# Generated by FakeRAM 2.0
VERSION 5.7 ;
BUSBITCHARS "[]" ;
PROPERTYDEFINITIONS
  MACRO width INTEGER ;
  MACRO depth INTEGER ;
  MACRO banks INTEGER ;
END PROPERTYDEFINITIONS
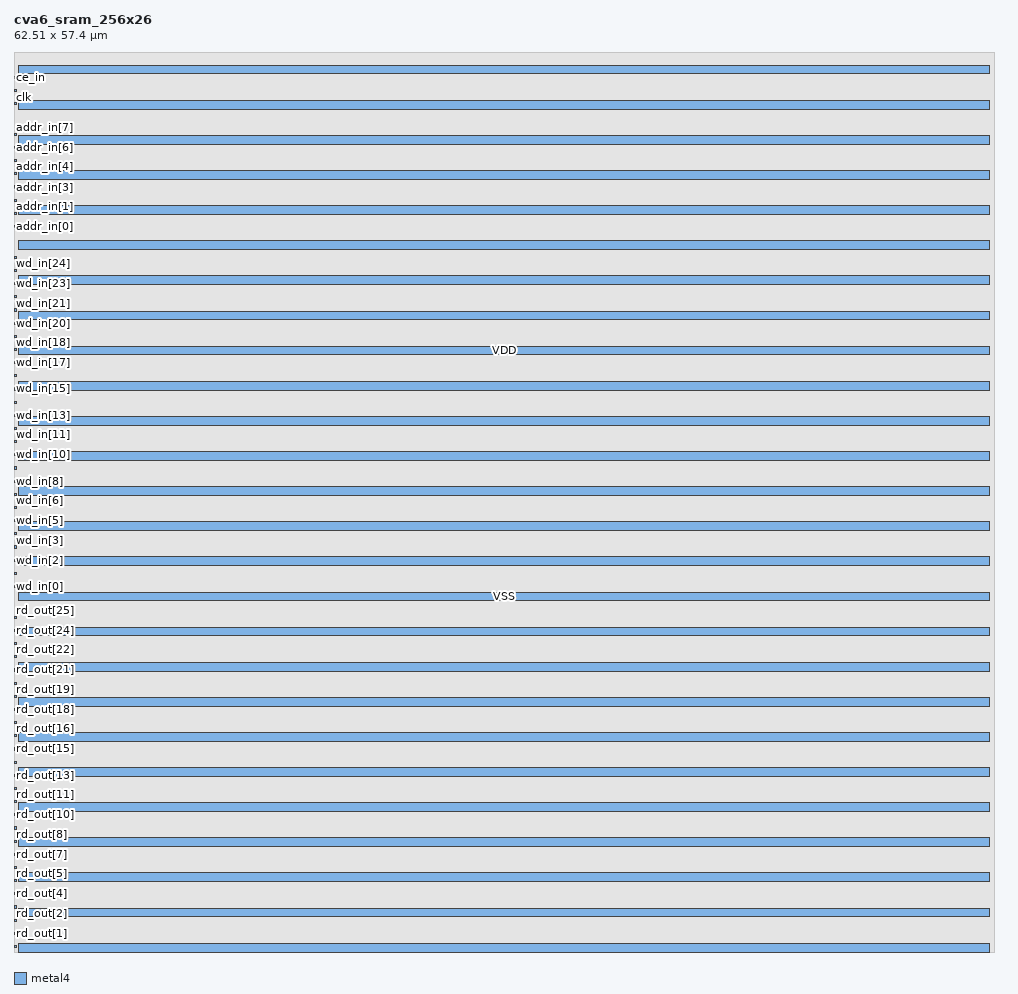
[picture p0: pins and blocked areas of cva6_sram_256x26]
MACRO cva6_sram_256x26
  PROPERTY width 26 ;
  PROPERTY depth 256 ;
  PROPERTY banks 1 ;
  FOREIGN cva6_sram_256x26 0 0 ;
  SYMMETRY X Y R90 ;
  SIZE 62.5100 BY 57.4000 ;
  CLASS BLOCK ;
  PIN rd_out[0]
    DIRECTION OUTPUT ;
    USE SIGNAL ;
    PORT
      LAYER metal4 ;
      RECT 0.00000 0.28000 0.14000 0.42000 ;
    END
  END rd_out[0]
  PIN rd_out[1]
    DIRECTION OUTPUT ;
    USE SIGNAL ;
    PORT
      LAYER metal4 ;
      RECT 0.00000 1.12000 0.14000 1.26000 ;
    END
  END rd_out[1]
  PIN rd_out[2]
    DIRECTION OUTPUT ;
    USE SIGNAL ;
    PORT
      LAYER metal4 ;
      RECT 0.00000 1.96000 0.14000 2.10000 ;
    END
  END rd_out[2]
  PIN rd_out[3]
    DIRECTION OUTPUT ;
    USE SIGNAL ;
    PORT
      LAYER metal4 ;
      RECT 0.00000 2.80000 0.14000 2.94000 ;
    END
  END rd_out[3]
  PIN rd_out[4]
    DIRECTION OUTPUT ;
    USE SIGNAL ;
    PORT
      LAYER metal4 ;
      RECT 0.00000 3.64000 0.14000 3.78000 ;
    END
  END rd_out[4]
  PIN rd_out[5]
    DIRECTION OUTPUT ;
    USE SIGNAL ;
    PORT
      LAYER metal4 ;
      RECT 0.00000 4.48000 0.14000 4.62000 ;
    END
  END rd_out[5]
  PIN rd_out[6]
    DIRECTION OUTPUT ;
    USE SIGNAL ;
    PORT
      LAYER metal4 ;
      RECT 0.00000 5.32000 0.14000 5.46000 ;
    END
  END rd_out[6]
  PIN rd_out[7]
    DIRECTION OUTPUT ;
    USE SIGNAL ;
    PORT
      LAYER metal4 ;
      RECT 0.00000 6.16000 0.14000 6.30000 ;
    END
  END rd_out[7]
  PIN rd_out[8]
    DIRECTION OUTPUT ;
    USE SIGNAL ;
    PORT
      LAYER metal4 ;
      RECT 0.00000 7.00000 0.14000 7.14000 ;
    END
  END rd_out[8]
  PIN rd_out[9]
    DIRECTION OUTPUT ;
    USE SIGNAL ;
    PORT
      LAYER metal4 ;
      RECT 0.00000 7.84000 0.14000 7.98000 ;
    END
  END rd_out[9]
  PIN rd_out[10]
    DIRECTION OUTPUT ;
    USE SIGNAL ;
    PORT
      LAYER metal4 ;
      RECT 0.00000 8.68000 0.14000 8.82000 ;
    END
  END rd_out[10]
  PIN rd_out[11]
    DIRECTION OUTPUT ;
    USE SIGNAL ;
    PORT
      LAYER metal4 ;
      RECT 0.00000 9.52000 0.14000 9.66000 ;
    END
  END rd_out[11]
  PIN rd_out[12]
    DIRECTION OUTPUT ;
    USE SIGNAL ;
    PORT
      LAYER metal4 ;
      RECT 0.00000 10.36000 0.14000 10.50000 ;
    END
  END rd_out[12]
  PIN rd_out[13]
    DIRECTION OUTPUT ;
    USE SIGNAL ;
    PORT
      LAYER metal4 ;
      RECT 0.00000 11.20000 0.14000 11.34000 ;
    END
  END rd_out[13]
  PIN rd_out[14]
    DIRECTION OUTPUT ;
    USE SIGNAL ;
    PORT
      LAYER metal4 ;
      RECT 0.00000 12.04000 0.14000 12.18000 ;
    END
  END rd_out[14]
  PIN rd_out[15]
    DIRECTION OUTPUT ;
    USE SIGNAL ;
    PORT
      LAYER metal4 ;
      RECT 0.00000 12.88000 0.14000 13.02000 ;
    END
  END rd_out[15]
  PIN rd_out[16]
    DIRECTION OUTPUT ;
    USE SIGNAL ;
    PORT
      LAYER metal4 ;
      RECT 0.00000 13.72000 0.14000 13.86000 ;
    END
  END rd_out[16]
  PIN rd_out[17]
    DIRECTION OUTPUT ;
    USE SIGNAL ;
    PORT
      LAYER metal4 ;
      RECT 0.00000 14.56000 0.14000 14.70000 ;
    END
  END rd_out[17]
  PIN rd_out[18]
    DIRECTION OUTPUT ;
    USE SIGNAL ;
    PORT
      LAYER metal4 ;
      RECT 0.00000 15.40000 0.14000 15.54000 ;
    END
  END rd_out[18]
  PIN rd_out[19]
    DIRECTION OUTPUT ;
    USE SIGNAL ;
    PORT
      LAYER metal4 ;
      RECT 0.00000 16.24000 0.14000 16.38000 ;
    END
  END rd_out[19]
  PIN rd_out[20]
    DIRECTION OUTPUT ;
    USE SIGNAL ;
    PORT
      LAYER metal4 ;
      RECT 0.00000 17.08000 0.14000 17.22000 ;
    END
  END rd_out[20]
  PIN rd_out[21]
    DIRECTION OUTPUT ;
    USE SIGNAL ;
    PORT
      LAYER metal4 ;
      RECT 0.00000 17.92000 0.14000 18.06000 ;
    END
  END rd_out[21]
  PIN rd_out[22]
    DIRECTION OUTPUT ;
    USE SIGNAL ;
    PORT
      LAYER metal4 ;
      RECT 0.00000 18.76000 0.14000 18.90000 ;
    END
  END rd_out[22]
  PIN rd_out[23]
    DIRECTION OUTPUT ;
    USE SIGNAL ;
    PORT
      LAYER metal4 ;
      RECT 0.00000 19.60000 0.14000 19.74000 ;
    END
  END rd_out[23]
  PIN rd_out[24]
    DIRECTION OUTPUT ;
    USE SIGNAL ;
    PORT
      LAYER metal4 ;
      RECT 0.00000 20.44000 0.14000 20.58000 ;
    END
  END rd_out[24]
  PIN rd_out[25]
    DIRECTION OUTPUT ;
    USE SIGNAL ;
    PORT
      LAYER metal4 ;
      RECT 0.00000 21.28000 0.14000 21.42000 ;
    END
  END rd_out[25]
  PIN wd_in[0]
    DIRECTION INPUT ;
    USE SIGNAL ;
    PORT
      LAYER metal4 ;
      RECT 0.00000 23.24000 0.14000 23.38000 ;
    END
  END wd_in[0]
  PIN wd_in[1]
    DIRECTION INPUT ;
    USE SIGNAL ;
    PORT
      LAYER metal4 ;
      RECT 0.00000 24.08000 0.14000 24.22000 ;
    END
  END wd_in[1]
  PIN wd_in[2]
    DIRECTION INPUT ;
    USE SIGNAL ;
    PORT
      LAYER metal4 ;
      RECT 0.00000 24.92000 0.14000 25.06000 ;
    END
  END wd_in[2]
  PIN wd_in[3]
    DIRECTION INPUT ;
    USE SIGNAL ;
    PORT
      LAYER metal4 ;
      RECT 0.00000 25.76000 0.14000 25.90000 ;
    END
  END wd_in[3]
  PIN wd_in[4]
    DIRECTION INPUT ;
    USE SIGNAL ;
    PORT
      LAYER metal4 ;
      RECT 0.00000 26.60000 0.14000 26.74000 ;
    END
  END wd_in[4]
  PIN wd_in[5]
    DIRECTION INPUT ;
    USE SIGNAL ;
    PORT
      LAYER metal4 ;
      RECT 0.00000 27.44000 0.14000 27.58000 ;
    END
  END wd_in[5]
  PIN wd_in[6]
    DIRECTION INPUT ;
    USE SIGNAL ;
    PORT
      LAYER metal4 ;
      RECT 0.00000 28.28000 0.14000 28.42000 ;
    END
  END wd_in[6]
  PIN wd_in[7]
    DIRECTION INPUT ;
    USE SIGNAL ;
    PORT
      LAYER metal4 ;
      RECT 0.00000 29.12000 0.14000 29.26000 ;
    END
  END wd_in[7]
  PIN wd_in[8]
    DIRECTION INPUT ;
    USE SIGNAL ;
    PORT
      LAYER metal4 ;
      RECT 0.00000 29.96000 0.14000 30.10000 ;
    END
  END wd_in[8]
  PIN wd_in[9]
    DIRECTION INPUT ;
    USE SIGNAL ;
    PORT
      LAYER metal4 ;
      RECT 0.00000 30.80000 0.14000 30.94000 ;
    END
  END wd_in[9]
  PIN wd_in[10]
    DIRECTION INPUT ;
    USE SIGNAL ;
    PORT
      LAYER metal4 ;
      RECT 0.00000 31.64000 0.14000 31.78000 ;
    END
  END wd_in[10]
  PIN wd_in[11]
    DIRECTION INPUT ;
    USE SIGNAL ;
    PORT
      LAYER metal4 ;
      RECT 0.00000 32.48000 0.14000 32.62000 ;
    END
  END wd_in[11]
  PIN wd_in[12]
    DIRECTION INPUT ;
    USE SIGNAL ;
    PORT
      LAYER metal4 ;
      RECT 0.00000 33.32000 0.14000 33.46000 ;
    END
  END wd_in[12]
  PIN wd_in[13]
    DIRECTION INPUT ;
    USE SIGNAL ;
    PORT
      LAYER metal4 ;
      RECT 0.00000 34.16000 0.14000 34.30000 ;
    END
  END wd_in[13]
  PIN wd_in[14]
    DIRECTION INPUT ;
    USE SIGNAL ;
    PORT
      LAYER metal4 ;
      RECT 0.00000 35.00000 0.14000 35.14000 ;
    END
  END wd_in[14]
  PIN wd_in[15]
    DIRECTION INPUT ;
    USE SIGNAL ;
    PORT
      LAYER metal4 ;
      RECT 0.00000 35.84000 0.14000 35.98000 ;
    END
  END wd_in[15]
  PIN wd_in[16]
    DIRECTION INPUT ;
    USE SIGNAL ;
    PORT
      LAYER metal4 ;
      RECT 0.00000 36.68000 0.14000 36.82000 ;
    END
  END wd_in[16]
  PIN wd_in[17]
    DIRECTION INPUT ;
    USE SIGNAL ;
    PORT
      LAYER metal4 ;
      RECT 0.00000 37.52000 0.14000 37.66000 ;
    END
  END wd_in[17]
  PIN wd_in[18]
    DIRECTION INPUT ;
    USE SIGNAL ;
    PORT
      LAYER metal4 ;
      RECT 0.00000 38.36000 0.14000 38.50000 ;
    END
  END wd_in[18]
  PIN wd_in[19]
    DIRECTION INPUT ;
    USE SIGNAL ;
    PORT
      LAYER metal4 ;
      RECT 0.00000 39.20000 0.14000 39.34000 ;
    END
  END wd_in[19]
  PIN wd_in[20]
    DIRECTION INPUT ;
    USE SIGNAL ;
    PORT
      LAYER metal4 ;
      RECT 0.00000 40.04000 0.14000 40.18000 ;
    END
  END wd_in[20]
  PIN wd_in[21]
    DIRECTION INPUT ;
    USE SIGNAL ;
    PORT
      LAYER metal4 ;
      RECT 0.00000 40.88000 0.14000 41.02000 ;
    END
  END wd_in[21]
  PIN wd_in[22]
    DIRECTION INPUT ;
    USE SIGNAL ;
    PORT
      LAYER metal4 ;
      RECT 0.00000 41.72000 0.14000 41.86000 ;
    END
  END wd_in[22]
  PIN wd_in[23]
    DIRECTION INPUT ;
    USE SIGNAL ;
    PORT
      LAYER metal4 ;
      RECT 0.00000 42.56000 0.14000 42.70000 ;
    END
  END wd_in[23]
  PIN wd_in[24]
    DIRECTION INPUT ;
    USE SIGNAL ;
    PORT
      LAYER metal4 ;
      RECT 0.00000 43.40000 0.14000 43.54000 ;
    END
  END wd_in[24]
  PIN wd_in[25]
    DIRECTION INPUT ;
    USE SIGNAL ;
    PORT
      LAYER metal4 ;
      RECT 0.00000 44.24000 0.14000 44.38000 ;
    END
  END wd_in[25]
  PIN addr_in[0]
    DIRECTION INPUT ;
    USE SIGNAL ;
    PORT
      LAYER metal4 ;
      RECT 0.00000 46.20000 0.14000 46.34000 ;
    END
  END addr_in[0]
  PIN addr_in[1]
    DIRECTION INPUT ;
    USE SIGNAL ;
    PORT
      LAYER metal4 ;
      RECT 0.00000 47.04000 0.14000 47.18000 ;
    END
  END addr_in[1]
  PIN addr_in[2]
    DIRECTION INPUT ;
    USE SIGNAL ;
    PORT
      LAYER metal4 ;
      RECT 0.00000 47.88000 0.14000 48.02000 ;
    END
  END addr_in[2]
  PIN addr_in[3]
    DIRECTION INPUT ;
    USE SIGNAL ;
    PORT
      LAYER metal4 ;
      RECT 0.00000 48.72000 0.14000 48.86000 ;
    END
  END addr_in[3]
  PIN addr_in[4]
    DIRECTION INPUT ;
    USE SIGNAL ;
    PORT
      LAYER metal4 ;
      RECT 0.00000 49.56000 0.14000 49.70000 ;
    END
  END addr_in[4]
  PIN addr_in[5]
    DIRECTION INPUT ;
    USE SIGNAL ;
    PORT
      LAYER metal4 ;
      RECT 0.00000 50.40000 0.14000 50.54000 ;
    END
  END addr_in[5]
  PIN addr_in[6]
    DIRECTION INPUT ;
    USE SIGNAL ;
    PORT
      LAYER metal4 ;
      RECT 0.00000 51.24000 0.14000 51.38000 ;
    END
  END addr_in[6]
  PIN addr_in[7]
    DIRECTION INPUT ;
    USE SIGNAL ;
    PORT
      LAYER metal4 ;
      RECT 0.00000 52.08000 0.14000 52.22000 ;
    END
  END addr_in[7]
  PIN we_in
    DIRECTION INPUT ;
    USE SIGNAL ;
    PORT
      LAYER metal4 ;
      RECT 0.00000 54.04000 0.14000 54.18000 ;
    END
  END we_in
  PIN clk
    DIRECTION INPUT ;
    USE SIGNAL ;
    PORT
      LAYER metal4 ;
      RECT 0.00000 54.88000 0.14000 55.02000 ;
    END
  END clk
  PIN ce_in
    DIRECTION INPUT ;
    USE SIGNAL ;
    PORT
      LAYER metal4 ;
      RECT 0.00000 55.72000 0.14000 55.86000 ;
    END
  END ce_in
  PIN VDD
    DIRECTION INOUT ;
    USE POWER ;
    PORT
      LAYER metal4 ;
      RECT 0.28000 2.24000 62.23000 2.80000 ;
      RECT 0.28000 6.72000 62.23000 7.28000 ;
      RECT 0.28000 11.20000 62.23000 11.76000 ;
      RECT 0.28000 15.68000 62.23000 16.24000 ;
      RECT 0.28000 20.16000 62.23000 20.72000 ;
      RECT 0.28000 24.64000 62.23000 25.20000 ;
      RECT 0.28000 29.12000 62.23000 29.68000 ;
      RECT 0.28000 33.60000 62.23000 34.16000 ;
      RECT 0.28000 38.08000 62.23000 38.64000 ;
      RECT 0.28000 42.56000 62.23000 43.12000 ;
      RECT 0.28000 47.04000 62.23000 47.60000 ;
      RECT 0.28000 51.52000 62.23000 52.08000 ;
      RECT 0.28000 56.00000 62.23000 56.56000 ;
    END
  END VDD
  PIN VSS
    DIRECTION INOUT ;
    USE GROUND ;
    PORT
      LAYER metal4 ;
      RECT 0.28000 0.00000 62.23000 0.56000 ;
      RECT 0.28000 4.48000 62.23000 5.04000 ;
      RECT 0.28000 8.96000 62.23000 9.52000 ;
      RECT 0.28000 13.44000 62.23000 14.00000 ;
      RECT 0.28000 17.92000 62.23000 18.48000 ;
      RECT 0.28000 22.40000 62.23000 22.96000 ;
      RECT 0.28000 26.88000 62.23000 27.44000 ;
      RECT 0.28000 31.36000 62.23000 31.92000 ;
      RECT 0.28000 35.84000 62.23000 36.40000 ;
      RECT 0.28000 40.32000 62.23000 40.88000 ;
      RECT 0.28000 44.80000 62.23000 45.36000 ;
      RECT 0.28000 49.28000 62.23000 49.84000 ;
      RECT 0.28000 53.76000 62.23000 54.32000 ;
    END
  END VSS
  OBS
    LAYER metal1 ;
    RECT 0 0 62.51000 57.40000 ;
    LAYER metal2 ;
    RECT 0 0 62.51000 57.40000 ;
    LAYER metal3 ;
    RECT 0 0 62.51000 57.40000 ;
    LAYER metal4 ;
    RECT 0 0 62.51000 57.40000 ;
  END
END cva6_sram_256x26

END LIBRARY
